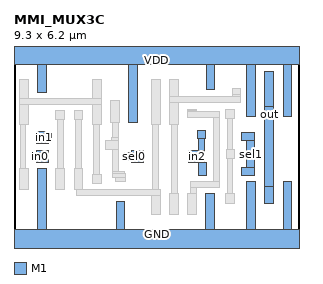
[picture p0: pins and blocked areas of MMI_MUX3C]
MACRO MMI_MUX3C
	CLASS CORE ;
	FOREIGN MMI_MUX3C 0 0 ;
	SIZE 9.3 BY 6.2 ;
	SYMMETRY X Y ;
	SITE CORE1 ;
	PIN out
		DIRECTION output ;
		USE SIGNAL ;
		PORT
			LAYER M1 ;
			RECT 8.19 4.43 8.47 5.575 ;
			LAYER M1 ;
			RECT 8.19 1.825 8.475 4.43 ;
			LAYER M1 ;
			RECT 8.19 1.26 8.47 1.825 ;
		END
		AntennaDiffArea 1.0164 ;
	END out
	PIN sel0
		DIRECTION input ;
		USE SIGNAL ;
		PORT
			LAYER M1 ;
			RECT 3.84 2.93 4.22 2.98 ;
			LAYER M1 ;
			RECT 3.595 2.65 4.22 2.93 ;
			LAYER M1 ;
			RECT 3.84 2.6 4.22 2.65 ;
		END
		AntennaGateArea 0.51975 ;
	END sel0
	PIN in1
		DIRECTION input ;
		USE SIGNAL ;
		PORT
			LAYER M1 ;
			RECT 0.74 3.55 1.12 3.6 ;
			LAYER M1 ;
			RECT 0.74 3.27 1.235 3.55 ;
			LAYER M1 ;
			RECT 0.74 3.22 1.12 3.27 ;
		END
		AntennaGateArea 0.3465 ;
	END in1
	PIN GND
		DIRECTION inout ;
		USE GROUND ;
		PORT
			LAYER M1 ;
			RECT 0.78 0.42 1.06 2.4 ;
			LAYER M1 ;
			RECT 3.335 0.42 3.62 1.31 ;
			LAYER M1 ;
			RECT 6.255 0.42 6.535 1.585 ;
			LAYER M1 ;
			RECT 7.6 0.42 7.88 1.96 ;
			LAYER M1 ;
			RECT 8.78 0.42 9.06 1.96 ;
			LAYER M1 ;
			RECT 0 -0.42 9.3 0.42 ;
		END
	END GND
	PIN in2
		DIRECTION input ;
		USE SIGNAL ;
		PORT
			LAYER M1 ;
			RECT 5.975 3.365 6.255 3.645 ;
			LAYER M1 ;
			RECT 6.03 2.975 6.22 3.365 ;
			LAYER M1 ;
			RECT 5.705 2.6 6.22 2.975 ;
			LAYER M1 ;
			RECT 6.005 2.185 6.285 2.6 ;
		END
		AntennaGateArea 0.3465 ;
	END in2
	PIN sel1
		DIRECTION input ;
		USE SIGNAL ;
		PORT
			LAYER M1 ;
			RECT 7.425 3.3 7.845 3.58 ;
			LAYER M1 ;
			RECT 7.59 2.44 7.845 3.3 ;
			LAYER M1 ;
			RECT 7.42 2.16 7.845 2.44 ;
		END
		AntennaGateArea 0.51975 ;
	END sel1
	PIN VDD
		DIRECTION inout ;
		USE POWER ;
		PORT
			LAYER M1 ;
			RECT 0 5.78 9.3 6.62 ;
			LAYER M1 ;
			RECT 0.78 4.88 1.06 5.78 ;
			LAYER M1 ;
			RECT 3.75 3.915 4.03 5.78 ;
			LAYER M1 ;
			RECT 6.275 4.965 6.555 5.78 ;
			LAYER M1 ;
			RECT 7.6 4.105 7.88 5.78 ;
			LAYER M1 ;
			RECT 8.78 4.105 9.06 5.78 ;
		END
	END VDD
	PIN in0
		DIRECTION input ;
		USE SIGNAL ;
		PORT
			LAYER M1 ;
			RECT 0.74 2.93 1.12 2.98 ;
			LAYER M1 ;
			RECT 0.595 2.65 1.12 2.93 ;
			LAYER M1 ;
			RECT 0.74 2.6 1.12 2.65 ;
		END
		AntennaGateArea 0.3465 ;
	END in0
	OBS
		LAYER M1 ;
		RECT 0.19 4.675 0.47 5.315 ;
		LAYER M1 ;
		RECT 2.57 4.675 2.85 5.315 ;
		LAYER M1 ;
		RECT 0.19 4.485 2.85 4.675 ;
		LAYER M1 ;
		RECT 0.19 3.845 0.47 4.485 ;
		LAYER M1 ;
		RECT 1.37 4 1.65 4.28 ;
		LAYER M1 ;
		RECT 1.965 4 2.245 4.28 ;
		LAYER M1 ;
		RECT 0.2 2.4 0.39 3.845 ;
		LAYER M1 ;
		RECT 1.435 2.4 1.625 4 ;
		LAYER M1 ;
		RECT 2.01 2.4 2.205 4 ;
		LAYER M1 ;
		RECT 2.57 3.845 2.85 4.485 ;
		LAYER M1 ;
		RECT 3.16 3.915 3.44 4.615 ;
		LAYER M1 ;
		RECT 0.19 1.7 0.47 2.4 ;
		LAYER M1 ;
		RECT 1.37 1.7 1.65 2.4 ;
		LAYER M1 ;
		RECT 1.96 1.705 2.24 2.4 ;
		LAYER M1 ;
		RECT 2.595 2.195 2.785 3.845 ;
		LAYER M1 ;
		RECT 3.2 3.415 3.395 3.915 ;
		LAYER M1 ;
		RECT 4.485 3.83 4.765 5.3 ;
		LAYER M1 ;
		RECT 5.075 4.74 5.355 5.3 ;
		LAYER M1 ;
		RECT 7.115 4.805 7.395 5 ;
		LAYER M1 ;
		RECT 7.115 4.74 7.4 4.805 ;
		LAYER M1 ;
		RECT 5.075 4.545 7.4 4.74 ;
		LAYER M1 ;
		RECT 5.075 3.83 5.355 4.545 ;
		LAYER M1 ;
		RECT 5.67 4.29 5.95 4.34 ;
		LAYER M1 ;
		RECT 5.67 4.26 5.955 4.29 ;
		LAYER M1 ;
		RECT 5.67 4.07 6.715 4.26 ;
		LAYER M1 ;
		RECT 5.67 4.06 5.95 4.07 ;
		LAYER M1 ;
		RECT 3.195 3.3 3.395 3.415 ;
		LAYER M1 ;
		RECT 2.985 3.02 3.395 3.3 ;
		LAYER M1 ;
		RECT 3.2 2.285 3.395 3.02 ;
		LAYER M1 ;
		RECT 3.2 2.24 3.59 2.285 ;
		LAYER M1 ;
		RECT 2.565 1.915 2.845 2.195 ;
		LAYER M1 ;
		RECT 3.2 2.09 3.63 2.24 ;
		LAYER M1 ;
		RECT 3.315 1.96 3.63 2.09 ;
		LAYER M1 ;
		RECT 2.595 1.91 2.785 1.915 ;
		LAYER M1 ;
		RECT 4.53 1.705 4.72 3.83 ;
		LAYER M1 ;
		RECT 1.96 1.7 4.765 1.705 ;
		LAYER M1 ;
		RECT 2.05 1.515 4.765 1.7 ;
		LAYER M1 ;
		RECT 5.125 1.585 5.32 3.83 ;
		LAYER M1 ;
		RECT 6.525 1.98 6.715 4.07 ;
		LAYER M1 ;
		RECT 6.915 4.04 7.195 4.32 ;
		LAYER M1 ;
		RECT 6.955 3.01 7.145 4.04 ;
		LAYER M1 ;
		RECT 6.93 2.73 7.21 3.01 ;
		LAYER M1 ;
		RECT 5.75 1.785 6.715 1.98 ;
		LAYER M1 ;
		RECT 5.75 1.585 5.945 1.785 ;
		LAYER M1 ;
		RECT 6.955 1.585 7.145 2.73 ;
		LAYER M1 ;
		RECT 4.485 0.885 4.765 1.515 ;
		LAYER M1 ;
		RECT 5.075 0.885 5.355 1.585 ;
		LAYER M1 ;
		RECT 5.665 0.885 5.945 1.585 ;
		LAYER M1 ;
		RECT 6.905 1.27 7.185 1.585 ;
	END
END MMI_MUX3C
